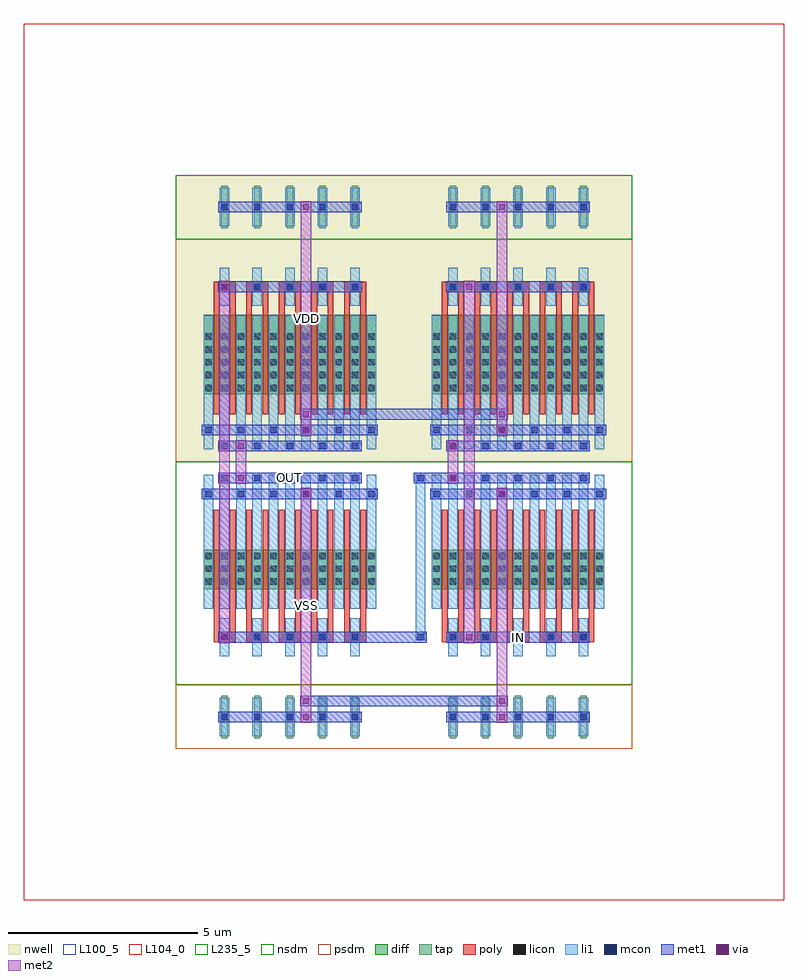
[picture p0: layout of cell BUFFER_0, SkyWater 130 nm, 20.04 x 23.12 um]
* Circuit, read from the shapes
.subckt BUFFER_0 IN OUT VDD VSS
XM1 OUT n1 VSS VSS sky130_fd_pr__nfet_01v8 w=1.05 l=0.15 m=10
XM2 n1 IN VSS VSS sky130_fd_pr__nfet_01v8 w=1.05 l=0.15 m=10
XM3 OUT n1 VDD VDD sky130_fd_pr__pfet_01v8 w=2.1 l=0.15 m=10
XM4 n1 IN VDD VDD sky130_fd_pr__pfet_01v8 w=2.1 l=0.15 m=10
.ends

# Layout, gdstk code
from math import pi, radians
import gdstk
lib = gdstk.Library(unit=1e-6, precision=1e-09)
def R(c, l, rs):  # rectangles x0, y0, x1, y1
    for r in rs: c.add(gdstk.rectangle(r[:2], r[2:], *l))
def A(c, l, x, y, w, h, nx, ny, dx, dy):  # array of equal rectangles
    R(c, l, [(x+i*dx, y+j*dy, x+i*dx+w, y+j*dy+h) for i in range(nx) for j in range(ny)])
def P(c, l, *ps):  # polygons
    for p in ps: c.add(gdstk.Polygon(p, *l))
nwell = (64, 20)
diff = (65, 20)
tap = (65, 44)
poly = (66, 20)
licon = (66, 44)
li1 = (67, 20)
mcon = (67, 44)
met1 = (68, 20)
via = (68, 44)
met2 = (69, 20)
nsdm = (93, 44)
psdm = (94, 20)
L100_5 = (100, 5)
L104_0 = (104, 0)
L235_5 = (235, 5)

nmos_s_29520189_x5_y1_16 = lib.new_cell('NMOS_S_29520189_X5_Y1_1676474850_1676474851')
R(nmos_s_29520189_x5_y1_16, diff, [(0.735,2.31,5.285,3.36)])
A(nmos_s_29520189_x5_y1_16, tap, 1.205, 6.16, 0.17, 1.12, 5, 1, 0.86, 0)
A(nmos_s_29520189_x5_y1_16, poly, 1, 1.26, 0.15, 3.36, 10, 1, 0.43, 0)
A(nmos_s_29520189_x5_y1_16, poly, 1, 4.485, 0.58, 0.27, 5, 1, 0.86, 0)
A(nmos_s_29520189_x5_y1_16, licon, 0.775, 2.39, 0.17, 0.17, 3, 3, 0.43, 0.34)
A(nmos_s_29520189_x5_y1_16, licon, 1.635, 2.39, 0.17, 0.17, 3, 3, 0.43, 0.34)
A(nmos_s_29520189_x5_y1_16, licon, 2.495, 2.39, 0.17, 0.17, 3, 3, 0.43, 0.34)
A(nmos_s_29520189_x5_y1_16, licon, 3.355, 2.39, 0.17, 0.17, 3, 3, 0.43, 0.34)
A(nmos_s_29520189_x5_y1_16, licon, 4.215, 2.39, 0.17, 0.17, 3, 3, 0.43, 0.34)
A(nmos_s_29520189_x5_y1_16, licon, 1.205, 4.535, 0.17, 0.17, 5, 2, 0.86, 2.1)
A(nmos_s_29520189_x5_y1_16, li1, 0.735, 0.335, 0.25, 3.53, 11, 1, 0.43, 0)
A(nmos_s_29520189_x5_y1_16, li1, 1.165, 4.115, 0.25, 1.01, 5, 2, 0.86, 2.1)
A(nmos_s_29520189_x5_y1_16, mcon, 1.205, 0.335, 0.17, 0.17, 5, 2, 0.86, 4.2)
A(nmos_s_29520189_x5_y1_16, mcon, 0.775, 0.755, 0.17, 0.17, 6, 1, 0.86, 0)
A(nmos_s_29520189_x5_y1_16, mcon, 1.205, 6.635, 0.17, 0.17, 5, 1, 0.86, 0)
R(nmos_s_29520189_x5_y1_16, met1, [(1.12,0.28,4.9,0.56), (0.69,0.7,5.33,0.98), (1.12,4.48,4.9,4.76), (1.12,6.58,4.9,6.86)])
R(nmos_s_29520189_x5_y1_16, via, [(3.365,0.765,3.515,0.915), (3.365,6.645,3.515,6.795)])
R(nmos_s_29520189_x5_y1_16, met2, [(3.3,0.68,3.58,6.88)])
R(nmos_s_29520189_x5_y1_16, nsdm, [(0,0,6.02,5.88)])
R(nmos_s_29520189_x5_y1_16, psdm, [(0,5.88,6.02,7.56)])
R(nmos_s_29520189_x5_y1_16, L100_5, [(0,0,6.02,7.56)])

pmos_s_61174647_x5_y1_16 = lib.new_cell('PMOS_S_61174647_X5_Y1_1676474851_1676474851')
R(pmos_s_61174647_x5_y1_16, nwell, [(0,0,6.02,7.56)])
R(pmos_s_61174647_x5_y1_16, diff, [(0.735,1.785,5.285,3.885)])
A(pmos_s_61174647_x5_y1_16, tap, 1.205, 6.16, 0.17, 1.12, 5, 1, 0.86, 0)
A(pmos_s_61174647_x5_y1_16, poly, 1, 1.26, 0.15, 3.36, 10, 1, 0.43, 0)
A(pmos_s_61174647_x5_y1_16, poly, 1, 4.485, 0.58, 0.27, 5, 1, 0.86, 0)
A(pmos_s_61174647_x5_y1_16, licon, 0.775, 1.865, 0.17, 0.17, 3, 5, 0.43, 0.34)
A(pmos_s_61174647_x5_y1_16, licon, 1.635, 1.865, 0.17, 0.17, 3, 5, 0.43, 0.34)
A(pmos_s_61174647_x5_y1_16, licon, 2.495, 1.865, 0.17, 0.17, 3, 5, 0.43, 0.34)
A(pmos_s_61174647_x5_y1_16, licon, 3.355, 1.865, 0.17, 0.17, 3, 5, 0.43, 0.34)
A(pmos_s_61174647_x5_y1_16, licon, 4.215, 1.865, 0.17, 0.17, 3, 5, 0.43, 0.34)
A(pmos_s_61174647_x5_y1_16, licon, 1.205, 4.535, 0.17, 0.17, 5, 2, 0.86, 2.1)
A(pmos_s_61174647_x5_y1_16, li1, 0.735, 0.335, 0.25, 3.53, 11, 1, 0.43, 0)
A(pmos_s_61174647_x5_y1_16, li1, 1.165, 4.115, 0.25, 1.01, 5, 2, 0.86, 2.1)
A(pmos_s_61174647_x5_y1_16, mcon, 1.205, 0.335, 0.17, 0.17, 5, 2, 0.86, 4.2)
A(pmos_s_61174647_x5_y1_16, mcon, 0.775, 0.755, 0.17, 0.17, 6, 1, 0.86, 0)
A(pmos_s_61174647_x5_y1_16, mcon, 1.205, 6.635, 0.17, 0.17, 5, 1, 0.86, 0)
R(pmos_s_61174647_x5_y1_16, met1, [(1.12,0.28,4.9,0.56), (0.69,0.7,5.33,0.98), (1.12,4.48,4.9,4.76), (1.12,6.58,4.9,6.86)])
R(pmos_s_61174647_x5_y1_16, via, [(3.365,0.765,3.515,0.915), (3.365,6.645,3.515,6.795)])
R(pmos_s_61174647_x5_y1_16, met2, [(3.3,0.68,3.58,6.88)])
R(pmos_s_61174647_x5_y1_16, nsdm, [(0,5.88,6.02,7.56)])
R(pmos_s_61174647_x5_y1_16, psdm, [(0,0,6.02,5.88)])
R(pmos_s_61174647_x5_y1_16, L100_5, [(0,0,6.02,7.56)])

stage2_inv_15241980_0_0_ = lib.new_cell('STAGE2_INV_15241980_0_0_1676474851')
R(stage2_inv_15241980_0_0_, li1, [(6.325,2.855,6.575,3.025), (6.325,2.855,6.575,3.025), (6.325,2.855,6.575,3.025), (6.325,2.855,6.575,3.025), (6.325,2.94,6.575,7.14), (6.325,7.055,6.575,7.225), (6.325,7.055,6.575,7.225), (6.325,7.055,6.575,7.225), (6.325,7.055,6.575,7.225)])
R(stage2_inv_15241980_0_0_, mcon, [(6.365,2.855,6.535,3.025), (6.365,2.855,6.535,3.025), (6.365,2.855,6.535,3.025), (6.365,2.855,6.535,3.025), (6.365,7.055,6.535,7.225), (6.365,7.055,6.535,7.225), (6.365,7.055,6.535,7.225), (6.365,7.055,6.535,7.225)])
R(stage2_inv_15241980_0_0_, met1, [(3.28,1.12,3.6,1.4), (3.28,1.12,3.6,1.4), (3.44,1.12,8.6,1.4), (8.44,1.12,8.76,1.4), (8.44,1.12,8.76,1.4), (1.13,2.8,1.45,3.08), (1.13,2.8,1.45,3.08), (1.13,2.8,1.45,3.08), (1.13,2.8,1.45,3.08), (1.13,2.8,1.45,3.08), (1.13,2.8,1.45,3.08), (4.73,2.8,6.45,3.08), (6.28,2.8,6.62,3.08), (6.28,2.8,6.62,3.08), (6.28,2.8,6.62,3.08), (6.28,2.8,6.62,3.08), (7.58,2.8,7.9,3.08), (7.58,2.8,7.9,3.08), (1.56,7,1.88,7.28), (1.56,7,1.88,7.28), (6.28,7,6.62,7.28), (6.28,7,6.62,7.28), (6.28,7,6.62,7.28), (6.28,7,6.62,7.28), (6.45,7,7.31,7.28), (7.15,7,7.47,7.28), (7.15,7,7.47,7.28), (1.56,7.84,1.88,8.12), (1.56,7.84,1.88,8.12), (7.15,7.84,7.47,8.12), (7.15,7.84,7.47,8.12), (3.28,8.68,3.6,8.96), (3.28,8.68,3.6,8.96), (3.44,8.68,8.6,8.96), (8.44,8.68,8.76,8.96), (8.44,8.68,8.76,8.96), (1.13,12.04,1.45,12.32), (1.13,12.04,1.45,12.32), (1.13,12.04,1.45,12.32), (1.13,12.04,1.45,12.32), (1.13,12.04,1.45,12.32), (1.13,12.04,1.45,12.32), (7.58,12.04,7.9,12.32), (7.58,12.04,7.9,12.32)])
P(stage2_inv_15241980_0_0_, met1, [(0,0),(0,0),(0,0),(0,0)],
  [(0,0),(0,0),(0,0),(0,0)],
  [(0,0),(0,0),(0,0),(0,0)],
  [(0,0),(0,0),(0,0),(0,0)],
  [(0,0),(0,0),(0,0),(0,0)],
  [(0,0),(0,0),(0,0),(0,0)],
  [(0,0),(0,0),(0,0),(0,0)],
  [(0,0),(0,0),(0,0),(0,0)])
R(stage2_inv_15241980_0_0_, via, [(3.365,1.185,3.515,1.335), (3.365,1.185,3.515,1.335), (8.525,1.185,8.675,1.335), (8.525,1.185,8.675,1.335), (1.215,2.865,1.365,3.015), (1.215,2.865,1.365,3.015), (1.215,2.865,1.365,3.015), (1.215,2.865,1.365,3.015), (1.215,2.865,1.365,3.015), (1.215,2.865,1.365,3.015), (7.665,2.865,7.815,3.015), (7.665,2.865,7.815,3.015), (1.645,7.065,1.795,7.215), (1.645,7.065,1.795,7.215), (7.235,7.065,7.385,7.215), (7.235,7.065,7.385,7.215), (1.645,7.905,1.795,8.055), (1.645,7.905,1.795,8.055), (7.235,7.905,7.385,8.055), (7.235,7.905,7.385,8.055), (3.365,8.745,3.515,8.895), (3.365,8.745,3.515,8.895), (8.525,8.745,8.675,8.895), (8.525,8.745,8.675,8.895), (1.215,12.105,1.365,12.255), (1.215,12.105,1.365,12.255), (1.215,12.105,1.365,12.255), (1.215,12.105,1.365,12.255), (1.215,12.105,1.365,12.255), (1.215,12.105,1.365,12.255), (7.665,12.105,7.815,12.255), (7.665,12.105,7.815,12.255)])
R(stage2_inv_15241980_0_0_, met2, [(3.3,1.1,3.58,1.42), (3.3,1.1,3.58,1.42), (8.46,1.1,8.74,1.42), (8.46,1.1,8.74,1.42), (1.15,2.78,1.43,3.1), (1.15,2.78,1.43,3.1), (1.15,2.78,1.43,3.1), (1.15,2.78,1.43,3.1), (1.15,2.78,1.43,3.1), (1.15,2.78,1.43,3.1), (7.6,2.78,7.88,3.1), (7.6,2.78,7.88,3.1), (1.15,2.94,1.43,12.18), (7.6,2.94,7.88,12.18), (1.58,6.98,1.86,7.3), (1.58,6.98,1.86,7.3), (7.17,6.98,7.45,7.3), (7.17,6.98,7.45,7.3), (1.58,7.14,1.86,7.98), (7.17,7.14,7.45,7.98), (1.58,7.82,1.86,8.14), (1.58,7.82,1.86,8.14), (7.17,7.82,7.45,8.14), (7.17,7.82,7.45,8.14), (3.3,8.66,3.58,8.98), (3.3,8.66,3.58,8.98), (8.46,8.66,8.74,8.98), (8.46,8.66,8.74,8.98), (1.15,12.02,1.43,12.34), (1.15,12.02,1.43,12.34), (1.15,12.02,1.43,12.34), (1.15,12.02,1.43,12.34), (1.15,12.02,1.43,12.34), (1.15,12.02,1.43,12.34), (7.6,12.02,7.88,12.34), (7.6,12.02,7.88,12.34)])
P(stage2_inv_15241980_0_0_, met2, [(0,0),(0,0),(0,0),(0,0)],
  [(0,0),(0,0),(0,0),(0,0)],
  [(0,0),(0,0),(0,0),(0,0)],
  [(0,0),(0,0),(0,0),(0,0)])
R(stage2_inv_15241980_0_0_, L235_5, [(0,0,12.04,15.12)])
stage2_inv_15241980_0_0_.add(gdstk.Reference(nmos_s_29520189_x5_y1_16, (12.04,7.56), rotation=pi))
stage2_inv_15241980_0_0_.add(gdstk.Reference(nmos_s_29520189_x5_y1_16, (0,7.56), x_reflection=True))
stage2_inv_15241980_0_0_.add(gdstk.Reference(pmos_s_61174647_x5_y1_16, (12.04,7.56), rotation=pi, x_reflection=True))
stage2_inv_15241980_0_0_.add(gdstk.Reference(pmos_s_61174647_x5_y1_16, (0,7.56)))

buffer_0 = lib.new_cell('BUFFER_0')
P(buffer_0, met1, [(0,0),(0,0),(0,0),(0,0)],
  [(0,0),(0,0),(0,0),(0,0)],
  [(0,0),(0,0),(0,0),(0,0)],
  [(0,0),(0,0),(0,0),(0,0)],
  [(0,0),(0,0),(0,0),(0,0)],
  [(0,0),(0,0),(0,0),(0,0)],
  [(0,0),(0,0),(0,0),(0,0)],
  [(0,0),(0,0),(0,0),(0,0)],
  [(0,0),(0,0),(0,0),(0,0)],
  [(0,0),(0,0),(0,0),(0,0)],
  [(0,0),(0,0),(0,0),(0,0)],
  [(0,0),(0,0),(0,0),(0,0)])
P(buffer_0, met2, [(0,0),(0,0),(0,0),(0,0)],
  [(0,0),(0,0),(0,0),(0,0)],
  [(0,0),(0,0),(0,0),(0,0)],
  [(0,0),(0,0),(0,0),(0,0)],
  [(0,0),(0,0),(0,0),(0,0)],
  [(0,0),(0,0),(0,0),(0,0)],
  [(0,0),(0,0),(0,0),(0,0)],
  [(0,0),(0,0),(0,0),(0,0)],
  [(0,0),(0,0),(0,0),(0,0)],
  [(0,0),(0,0),(0,0),(0,0)],
  [(0,0),(0,0),(0,0),(0,0)],
  [(0,0),(0,0),(0,0),(0,0)])
R(buffer_0, L104_0, [(-4,-4,16.04,19.12)])
R(buffer_0, L235_5, [(0,0,12.04,15.12)])
buffer_0.add(gdstk.Reference(stage2_inv_15241980_0_0_, (0,0)))
buffer_0.add(gdstk.Label('VSS', (3.44,3.78), layer=69, texttype=5))
buffer_0.add(gdstk.Label('VDD', (3.44,11.34), layer=69, texttype=5))
buffer_0.add(gdstk.Label('IN', (9.03,2.94), layer=68, texttype=5))
buffer_0.add(gdstk.Label('OUT', (3.01,7.14), layer=68, texttype=5))

lib.write_gds('BUFFER_0.gds')
